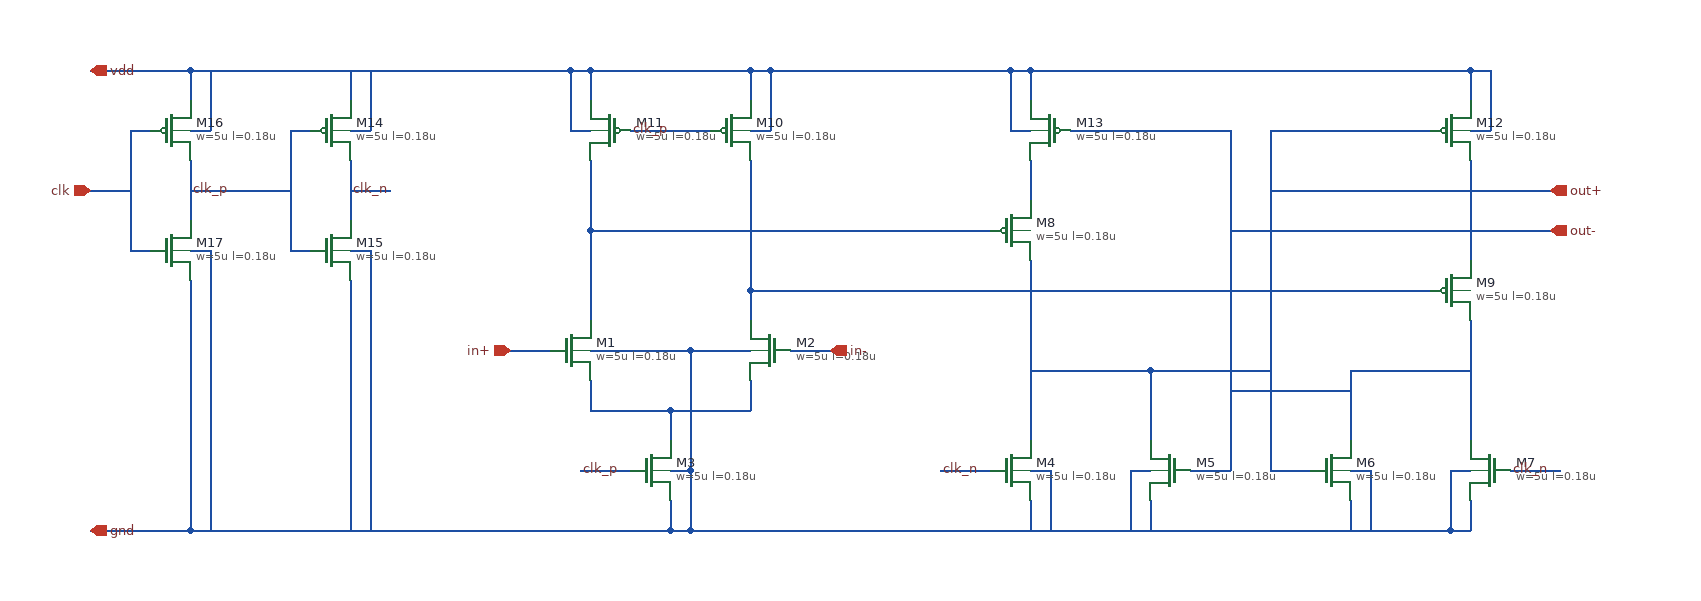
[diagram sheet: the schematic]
v {xschem version=2.9.7 file_version=1.1}
G {}
V {}
S {}
E {}
N -540 -230 -540 -200 {lab=#net1}
N -460 -200 -380 -200 {lab=#net1}
N -380 -230 -380 -200 {lab=#net1}
N -460 -200 -460 -170 {lab=#net1}
N -440 -260 -380 -260 {lab=vdd}
N -460 -110 -460 -80 {lab=vdd}
N -460 -80 -440 -80 {lab=vdd}
N -440 -140 -440 -80 {lab=vdd}
N -460 -140 -440 -140 {lab=vdd}
N 0 -140 20 -140 {lab=vdd}
N 320 -140 340 -140 {lab=vdd}
N 140 -140 180 -140 {lab=out+}
N 60 -140 100 -140 {lab=out-}
N 20 -200 20 -170 {lab=out+}
N -100 -240 20 -240 {lab=out+}
N -100 -200 -100 -170 {lab=out+}
N 220 -200 220 -170 {lab=out-}
N 220 -240 340 -240 {lab=out-}
N 340 -200 340 -170 {lab=out-}
N -380 -320 300 -320 {lab=#net2}
N -540 -380 -140 -380 {lab=#net3}
N -100 -350 -100 -200 {lab=out+}
N 340 -290 340 -200 {lab=out-}
N -380 -450 -380 -320 {lab=#net2}
N -540 -450 -540 -380 {lab=#net3}
N -500 -480 -420 -480 {lab=clk_p}
N -380 -480 -360 -480 {lab=vdd}
N -360 -540 -360 -480 {lab=vdd}
N -380 -540 -360 -540 {lab=vdd}
N -380 -540 -380 -510 {lab=vdd}
N -560 -480 -540 -480 {lab=vdd}
N -560 -540 -560 -480 {lab=vdd}
N -560 -540 -540 -540 {lab=vdd}
N -540 -540 -540 -510 {lab=vdd}
N -540 -540 -380 -540 {lab=vdd}
N -120 -480 -100 -480 {lab=vdd}
N -120 -540 -120 -480 {lab=vdd}
N -120 -540 -100 -540 {lab=vdd}
N -100 -540 -100 -510 {lab=vdd}
N -360 -540 -120 -540 {lab=vdd}
N 340 -540 360 -540 {lab=vdd}
N 360 -540 360 -480 {lab=vdd}
N 340 -480 360 -480 {lab=vdd}
N 340 -540 340 -510 {lab=vdd}
N -100 -450 -100 -410 {lab=#net4}
N 340 -450 340 -350 {lab=#net5}
N 100 -480 100 -140 {lab=out-}
N -60 -480 100 -480 {lab=out-}
N 140 -480 140 -140 {lab=out+}
N 140 -480 300 -480 {lab=out+}
N -100 -110 -100 -80 {lab=vdd}
N -100 -80 -80 -80 {lab=vdd}
N 220 -110 220 -80 {lab=vdd}
N 220 -80 240 -80 {lab=vdd}
N 20 -110 20 -80 {lab=vdd}
N 0 -80 20 -80 {lab=vdd}
N 340 -110 340 -80 {lab=vdd}
N 320 -80 340 -80 {lab=vdd}
N 320 -140 320 -80 {lab=vdd}
N 240 -140 240 -80 {lab=vdd}
N 0 -140 -0 -80 {lab=vdd}
N -80 -140 -80 -80 {lab=vdd}
N -540 -200 -460 -200 {lab=#net1}
N -540 -260 -440 -260 {lab=vdd}
N -440 -260 -440 -140 {lab=vdd}
N -100 -540 340 -540 {lab=vdd}
N 220 -140 240 -140 {lab=vdd}
N -100 -140 -80 -140 {lab=vdd}
N -440 -80 320 -80 {lab=vdd}
N 20 -240 20 -200 {lab=out+}
N 220 -240 220 -200 {lab=out-}
N 20 -240 140 -240 {lab=out+}
N 100 -220 220 -220 {lab=out-}
N 140 -420 420 -420 {lab=out+}
N 100 -380 420 -380 {lab=out-}
N -190 -140 -140 -140 {lab=clk_n}
N 380 -140 430 -140 {lab=clk_n}
N -550 -140 -500 -140 {lab=clk_p}
N -380 -320 -380 -290 {lab=#net2}
N -540 -380 -540 -290 {lab=#net3}
N -340 -260 -300 -260 {lab=in-}
N -620 -260 -580 -260 {lab=in+}
N -780 -450 -780 -390 {lab=clk_n}
N -780 -420 -740 -420 {lab=clk_n}
N -840 -360 -820 -360 {lab=clk_p}
N -840 -480 -840 -360 {lab=clk_p}
N -840 -480 -820 -480 {lab=clk_p}
N -940 -450 -940 -390 {lab=clk_p}
N -940 -420 -840 -420 {lab=clk_p}
N -1000 -360 -980 -360 {lab=clk}
N -1000 -480 -1000 -360 {lab=clk}
N -1000 -480 -980 -480 {lab=clk}
N -940 -540 -940 -510 {lab=vdd}
N -940 -540 -560 -540 {lab=vdd}
N -940 -480 -920 -480 {lab=vdd}
N -920 -540 -920 -480 {lab=vdd}
N -780 -540 -780 -510 {lab=vdd}
N -780 -480 -760 -480 {lab=vdd}
N -760 -540 -760 -480 {lab=vdd}
N -780 -360 -760 -360 {lab=vdd}
N -760 -360 -760 -80 {lab=vdd}
N -940 -330 -940 -80 {lab=vdd}
N -940 -80 -460 -80 {lab=vdd}
N -940 -360 -920 -360 {lab=vdd}
N -920 -360 -920 -80 {lab=vdd}
N -780 -330 -780 -80 {lab=vdd}
N -1040 -420 -1000 -420 {lab=clk}
N -1040 -540 -940 -540 {lab=vdd}
N -1040 -80 -940 -80 {lab=vdd}
C {nmos4.sym} -560 -260 0 0 {name=M1 model=nmos w=5u l=0.18u m=1}
C {nmos4.sym} -360 -260 0 1 {name=M2 model=nmos w=5u l=0.18u m=1}
C {nmos4.sym} -480 -140 0 0 {name=M3 model=nmos w=5u l=0.18u m=1}
C {nmos4.sym} -120 -140 0 0 {name=M4 model=nmos w=5u l=0.18u m=1}
C {nmos4.sym} 40 -140 0 1 {name=M5 model=nmos w=5u l=0.18u m=1}
C {nmos4.sym} 200 -140 0 0 {name=M6 model=nmos w=5u l=0.18u m=1}
C {nmos4.sym} 360 -140 0 1 {name=M7 model=nmos w=5u l=0.18u m=1}
C {pmos4.sym} -120 -380 0 0 {name=M8 model=pmos w=5u l=0.18u m=1}
C {pmos4.sym} 320 -320 0 0 {name=M9 model=pmos w=5u l=0.18u m=1}
C {pmos4.sym} -400 -480 0 0 {name=M10 model=pmos w=5u l=0.18u m=1}
C {pmos4.sym} -520 -480 0 1 {name=M11 model=pmos w=5u l=0.18u m=1}
C {pmos4.sym} 320 -480 0 0 {name=M12 model=pmos w=5u l=0.18u m=1}
C {pmos4.sym} -80 -480 0 1 {name=M13 model=pmos w=5u l=0.18u m=1}
C {opin.sym} 420 -420 0 0 {name=p1 lab=out+}
C {opin.sym} 420 -380 0 0 {name=p2 lab=out-}
C {lab_wire.sym} -190 -140 0 1 {name=l1 sig_type=std_logic lab=clk_n}
C {lab_wire.sym} 380 -140 0 1 {name=l2 sig_type=std_logic lab=clk_n}
C {lab_wire.sym} -550 -140 0 1 {name=l3 sig_type=std_logic lab=clk_p}
C {lab_wire.sym} -500 -480 0 1 {name=l4 sig_type=std_logic lab=clk_p}
C {ipin.sym} -620 -260 0 0 {name=p3 lab=in+}
C {ipin.sym} -300 -260 0 1 {name=p4 lab=in-}
C {pmos4.sym} -800 -480 0 0 {name=M14 model=pmos w=5u l=0.18u m=1}
C {nmos4.sym} -800 -360 0 0 {name=M15 model=nmos w=5u l=0.18u m=1}
C {pmos4.sym} -960 -480 0 0 {name=M16 model=pmos w=5u l=0.18u m=1}
C {nmos4.sym} -960 -360 0 0 {name=M17 model=nmos w=5u l=0.18u m=1}
C {lab_wire.sym} -780 -420 0 1 {name=l5 sig_type=std_logic lab=clk_n}
C {lab_wire.sym} -940 -420 0 1 {name=l6 sig_type=std_logic lab=clk_p}
C {ipin.sym} -1040 -420 0 0 {name=p5 lab=clk}
C {iopin.sym} -1040 -540 0 1 {name=p6 lab=vdd}
C {iopin.sym} -1040 -80 0 1 {name=p7 lab=gnd}
